# Generated by FakeRAM 2.0 (routing-friendly)
VERSION 5.7 ;
BUSBITCHARS "[]" ;
PROPERTYDEFINITIONS
  MACRO width INTEGER ;
  MACRO depth INTEGER ;
  MACRO banks INTEGER ;
END PROPERTYDEFINITIONS
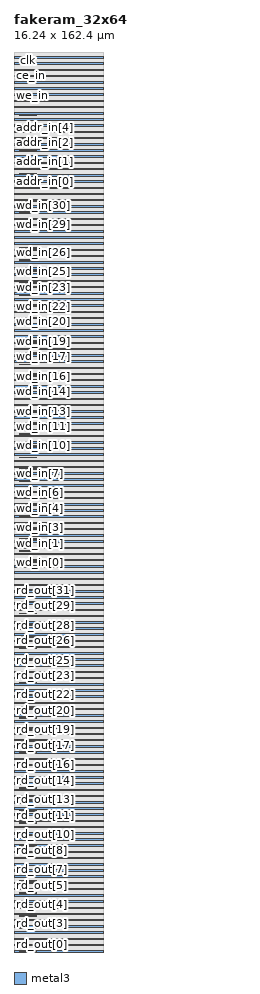
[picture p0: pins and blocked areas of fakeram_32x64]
MACRO fakeram_32x64
  PROPERTY width 32 ;
  PROPERTY depth 64 ;
  PROPERTY banks 1 ;
  FOREIGN fakeram_32x64 0 0 ;
  SYMMETRY X Y R90 ;
  SIZE 16.240 BY 162.400 ;
  CLASS BLOCK ;
  PIN rd_out[0]
    DIRECTION OUTPUT ;
    USE SIGNAL ;
    PORT
      LAYER metal3 ;
      RECT 1.000 0.140 3.000 0.210 ;
    END
    PORT
      LAYER metal3 ;
      RECT 1.000 0.105 4.000 0.245 ;
    END
  END rd_out[0]
  PIN rd_out[1]
    DIRECTION OUTPUT ;
    USE SIGNAL ;
    PORT
      LAYER metal3 ;
      RECT 1.000 2.240 3.000 2.310 ;
    END
    PORT
      LAYER metal3 ;
      RECT 1.000 2.205 4.000 2.345 ;
    END
  END rd_out[1]
  PIN rd_out[2]
    DIRECTION OUTPUT ;
    USE SIGNAL ;
    PORT
      LAYER metal3 ;
      RECT 1.000 4.340 3.000 4.410 ;
    END
    PORT
      LAYER metal3 ;
      RECT 1.000 4.305 4.000 4.445 ;
    END
  END rd_out[2]
  PIN rd_out[3]
    DIRECTION OUTPUT ;
    USE SIGNAL ;
    PORT
      LAYER metal3 ;
      RECT 1.000 6.440 3.000 6.510 ;
    END
    PORT
      LAYER metal3 ;
      RECT 1.000 6.405 4.000 6.545 ;
    END
  END rd_out[3]
  PIN rd_out[4]
    DIRECTION OUTPUT ;
    USE SIGNAL ;
    PORT
      LAYER metal3 ;
      RECT 1.000 8.540 3.000 8.610 ;
    END
    PORT
      LAYER metal3 ;
      RECT 1.000 8.505 4.000 8.645 ;
    END
  END rd_out[4]
  PIN rd_out[5]
    DIRECTION OUTPUT ;
    USE SIGNAL ;
    PORT
      LAYER metal3 ;
      RECT 1.000 10.640 3.000 10.710 ;
    END
    PORT
      LAYER metal3 ;
      RECT 1.000 10.605 4.000 10.745 ;
    END
  END rd_out[5]
  PIN rd_out[6]
    DIRECTION OUTPUT ;
    USE SIGNAL ;
    PORT
      LAYER metal3 ;
      RECT 1.000 12.740 3.000 12.810 ;
    END
    PORT
      LAYER metal3 ;
      RECT 1.000 12.705 4.000 12.845 ;
    END
  END rd_out[6]
  PIN rd_out[7]
    DIRECTION OUTPUT ;
    USE SIGNAL ;
    PORT
      LAYER metal3 ;
      RECT 1.000 14.840 3.000 14.910 ;
    END
    PORT
      LAYER metal3 ;
      RECT 1.000 14.805 4.000 14.945 ;
    END
  END rd_out[7]
  PIN rd_out[8]
    DIRECTION OUTPUT ;
    USE SIGNAL ;
    PORT
      LAYER metal3 ;
      RECT 1.000 16.940 3.000 17.010 ;
    END
    PORT
      LAYER metal3 ;
      RECT 1.000 16.905 4.000 17.045 ;
    END
  END rd_out[8]
  PIN rd_out[9]
    DIRECTION OUTPUT ;
    USE SIGNAL ;
    PORT
      LAYER metal3 ;
      RECT 1.000 19.040 3.000 19.110 ;
    END
    PORT
      LAYER metal3 ;
      RECT 1.000 19.005 4.000 19.145 ;
    END
  END rd_out[9]
  PIN rd_out[10]
    DIRECTION OUTPUT ;
    USE SIGNAL ;
    PORT
      LAYER metal3 ;
      RECT 1.000 21.140 3.000 21.210 ;
    END
    PORT
      LAYER metal3 ;
      RECT 1.000 21.105 4.000 21.245 ;
    END
  END rd_out[10]
  PIN rd_out[11]
    DIRECTION OUTPUT ;
    USE SIGNAL ;
    PORT
      LAYER metal3 ;
      RECT 1.000 23.240 3.000 23.310 ;
    END
    PORT
      LAYER metal3 ;
      RECT 1.000 23.205 4.000 23.345 ;
    END
  END rd_out[11]
  PIN rd_out[12]
    DIRECTION OUTPUT ;
    USE SIGNAL ;
    PORT
      LAYER metal3 ;
      RECT 1.000 25.340 3.000 25.410 ;
    END
    PORT
      LAYER metal3 ;
      RECT 1.000 25.305 4.000 25.445 ;
    END
  END rd_out[12]
  PIN rd_out[13]
    DIRECTION OUTPUT ;
    USE SIGNAL ;
    PORT
      LAYER metal3 ;
      RECT 1.000 27.440 3.000 27.510 ;
    END
    PORT
      LAYER metal3 ;
      RECT 1.000 27.405 4.000 27.545 ;
    END
  END rd_out[13]
  PIN rd_out[14]
    DIRECTION OUTPUT ;
    USE SIGNAL ;
    PORT
      LAYER metal3 ;
      RECT 1.000 29.540 3.000 29.610 ;
    END
    PORT
      LAYER metal3 ;
      RECT 1.000 29.505 4.000 29.645 ;
    END
  END rd_out[14]
  PIN rd_out[15]
    DIRECTION OUTPUT ;
    USE SIGNAL ;
    PORT
      LAYER metal3 ;
      RECT 1.000 31.640 3.000 31.710 ;
    END
    PORT
      LAYER metal3 ;
      RECT 1.000 31.605 4.000 31.745 ;
    END
  END rd_out[15]
  PIN rd_out[16]
    DIRECTION OUTPUT ;
    USE SIGNAL ;
    PORT
      LAYER metal3 ;
      RECT 1.000 33.740 3.000 33.810 ;
    END
    PORT
      LAYER metal3 ;
      RECT 1.000 33.705 4.000 33.845 ;
    END
  END rd_out[16]
  PIN rd_out[17]
    DIRECTION OUTPUT ;
    USE SIGNAL ;
    PORT
      LAYER metal3 ;
      RECT 1.000 35.840 3.000 35.910 ;
    END
    PORT
      LAYER metal3 ;
      RECT 1.000 35.805 4.000 35.945 ;
    END
  END rd_out[17]
  PIN rd_out[18]
    DIRECTION OUTPUT ;
    USE SIGNAL ;
    PORT
      LAYER metal3 ;
      RECT 1.000 37.940 3.000 38.010 ;
    END
    PORT
      LAYER metal3 ;
      RECT 1.000 37.905 4.000 38.045 ;
    END
  END rd_out[18]
  PIN rd_out[19]
    DIRECTION OUTPUT ;
    USE SIGNAL ;
    PORT
      LAYER metal3 ;
      RECT 1.000 40.040 3.000 40.110 ;
    END
    PORT
      LAYER metal3 ;
      RECT 1.000 40.005 4.000 40.145 ;
    END
  END rd_out[19]
  PIN rd_out[20]
    DIRECTION OUTPUT ;
    USE SIGNAL ;
    PORT
      LAYER metal3 ;
      RECT 1.000 42.140 3.000 42.210 ;
    END
    PORT
      LAYER metal3 ;
      RECT 1.000 42.105 4.000 42.245 ;
    END
  END rd_out[20]
  PIN rd_out[21]
    DIRECTION OUTPUT ;
    USE SIGNAL ;
    PORT
      LAYER metal3 ;
      RECT 1.000 44.240 3.000 44.310 ;
    END
    PORT
      LAYER metal3 ;
      RECT 1.000 44.205 4.000 44.345 ;
    END
  END rd_out[21]
  PIN rd_out[22]
    DIRECTION OUTPUT ;
    USE SIGNAL ;
    PORT
      LAYER metal3 ;
      RECT 1.000 46.340 3.000 46.410 ;
    END
    PORT
      LAYER metal3 ;
      RECT 1.000 46.305 4.000 46.445 ;
    END
  END rd_out[22]
  PIN rd_out[23]
    DIRECTION OUTPUT ;
    USE SIGNAL ;
    PORT
      LAYER metal3 ;
      RECT 1.000 48.440 3.000 48.510 ;
    END
    PORT
      LAYER metal3 ;
      RECT 1.000 48.405 4.000 48.545 ;
    END
  END rd_out[23]
  PIN rd_out[24]
    DIRECTION OUTPUT ;
    USE SIGNAL ;
    PORT
      LAYER metal3 ;
      RECT 1.000 50.540 3.000 50.610 ;
    END
    PORT
      LAYER metal3 ;
      RECT 1.000 50.505 4.000 50.645 ;
    END
  END rd_out[24]
  PIN rd_out[25]
    DIRECTION OUTPUT ;
    USE SIGNAL ;
    PORT
      LAYER metal3 ;
      RECT 1.000 52.640 3.000 52.710 ;
    END
    PORT
      LAYER metal3 ;
      RECT 1.000 52.605 4.000 52.745 ;
    END
  END rd_out[25]
  PIN rd_out[26]
    DIRECTION OUTPUT ;
    USE SIGNAL ;
    PORT
      LAYER metal3 ;
      RECT 1.000 54.740 3.000 54.810 ;
    END
    PORT
      LAYER metal3 ;
      RECT 1.000 54.705 4.000 54.845 ;
    END
  END rd_out[26]
  PIN rd_out[27]
    DIRECTION OUTPUT ;
    USE SIGNAL ;
    PORT
      LAYER metal3 ;
      RECT 1.000 56.840 3.000 56.910 ;
    END
    PORT
      LAYER metal3 ;
      RECT 1.000 56.805 4.000 56.945 ;
    END
  END rd_out[27]
  PIN rd_out[28]
    DIRECTION OUTPUT ;
    USE SIGNAL ;
    PORT
      LAYER metal3 ;
      RECT 1.000 58.940 3.000 59.010 ;
    END
    PORT
      LAYER metal3 ;
      RECT 1.000 58.905 4.000 59.045 ;
    END
  END rd_out[28]
  PIN rd_out[29]
    DIRECTION OUTPUT ;
    USE SIGNAL ;
    PORT
      LAYER metal3 ;
      RECT 1.000 61.040 3.000 61.110 ;
    END
    PORT
      LAYER metal3 ;
      RECT 1.000 61.005 4.000 61.145 ;
    END
  END rd_out[29]
  PIN rd_out[30]
    DIRECTION OUTPUT ;
    USE SIGNAL ;
    PORT
      LAYER metal3 ;
      RECT 1.000 63.140 3.000 63.210 ;
    END
    PORT
      LAYER metal3 ;
      RECT 1.000 63.105 4.000 63.245 ;
    END
  END rd_out[30]
  PIN rd_out[31]
    DIRECTION OUTPUT ;
    USE SIGNAL ;
    PORT
      LAYER metal3 ;
      RECT 1.000 65.240 3.000 65.310 ;
    END
    PORT
      LAYER metal3 ;
      RECT 1.000 65.205 4.000 65.345 ;
    END
  END rd_out[31]
  PIN wd_in[0]
    DIRECTION INPUT ;
    USE SIGNAL ;
    PORT
      LAYER metal3 ;
      RECT 1.000 70.280 3.000 70.350 ;
    END
    PORT
      LAYER metal3 ;
      RECT 1.000 70.245 4.000 70.385 ;
    END
  END wd_in[0]
  PIN wd_in[1]
    DIRECTION INPUT ;
    USE SIGNAL ;
    PORT
      LAYER metal3 ;
      RECT 1.000 72.380 3.000 72.450 ;
    END
    PORT
      LAYER metal3 ;
      RECT 1.000 72.345 4.000 72.485 ;
    END
  END wd_in[1]
  PIN wd_in[2]
    DIRECTION INPUT ;
    USE SIGNAL ;
    PORT
      LAYER metal3 ;
      RECT 1.000 74.480 3.000 74.550 ;
    END
    PORT
      LAYER metal3 ;
      RECT 1.000 74.445 4.000 74.585 ;
    END
  END wd_in[2]
  PIN wd_in[3]
    DIRECTION INPUT ;
    USE SIGNAL ;
    PORT
      LAYER metal3 ;
      RECT 1.000 76.580 3.000 76.650 ;
    END
    PORT
      LAYER metal3 ;
      RECT 1.000 76.545 4.000 76.685 ;
    END
  END wd_in[3]
  PIN wd_in[4]
    DIRECTION INPUT ;
    USE SIGNAL ;
    PORT
      LAYER metal3 ;
      RECT 1.000 78.680 3.000 78.750 ;
    END
    PORT
      LAYER metal3 ;
      RECT 1.000 78.645 4.000 78.785 ;
    END
  END wd_in[4]
  PIN wd_in[5]
    DIRECTION INPUT ;
    USE SIGNAL ;
    PORT
      LAYER metal3 ;
      RECT 1.000 80.780 3.000 80.850 ;
    END
    PORT
      LAYER metal3 ;
      RECT 1.000 80.745 4.000 80.885 ;
    END
  END wd_in[5]
  PIN wd_in[6]
    DIRECTION INPUT ;
    USE SIGNAL ;
    PORT
      LAYER metal3 ;
      RECT 1.000 82.880 3.000 82.950 ;
    END
    PORT
      LAYER metal3 ;
      RECT 1.000 82.845 4.000 82.985 ;
    END
  END wd_in[6]
  PIN wd_in[7]
    DIRECTION INPUT ;
    USE SIGNAL ;
    PORT
      LAYER metal3 ;
      RECT 1.000 84.980 3.000 85.050 ;
    END
    PORT
      LAYER metal3 ;
      RECT 1.000 84.945 4.000 85.085 ;
    END
  END wd_in[7]
  PIN wd_in[8]
    DIRECTION INPUT ;
    USE SIGNAL ;
    PORT
      LAYER metal3 ;
      RECT 1.000 87.080 3.000 87.150 ;
    END
    PORT
      LAYER metal3 ;
      RECT 1.000 87.045 4.000 87.185 ;
    END
  END wd_in[8]
  PIN wd_in[9]
    DIRECTION INPUT ;
    USE SIGNAL ;
    PORT
      LAYER metal3 ;
      RECT 1.000 89.180 3.000 89.250 ;
    END
    PORT
      LAYER metal3 ;
      RECT 1.000 89.145 4.000 89.285 ;
    END
  END wd_in[9]
  PIN wd_in[10]
    DIRECTION INPUT ;
    USE SIGNAL ;
    PORT
      LAYER metal3 ;
      RECT 1.000 91.280 3.000 91.350 ;
    END
    PORT
      LAYER metal3 ;
      RECT 1.000 91.245 4.000 91.385 ;
    END
  END wd_in[10]
  PIN wd_in[11]
    DIRECTION INPUT ;
    USE SIGNAL ;
    PORT
      LAYER metal3 ;
      RECT 1.000 93.380 3.000 93.450 ;
    END
    PORT
      LAYER metal3 ;
      RECT 1.000 93.345 4.000 93.485 ;
    END
  END wd_in[11]
  PIN wd_in[12]
    DIRECTION INPUT ;
    USE SIGNAL ;
    PORT
      LAYER metal3 ;
      RECT 1.000 95.480 3.000 95.550 ;
    END
    PORT
      LAYER metal3 ;
      RECT 1.000 95.445 4.000 95.585 ;
    END
  END wd_in[12]
  PIN wd_in[13]
    DIRECTION INPUT ;
    USE SIGNAL ;
    PORT
      LAYER metal3 ;
      RECT 1.000 97.580 3.000 97.650 ;
    END
    PORT
      LAYER metal3 ;
      RECT 1.000 97.545 4.000 97.685 ;
    END
  END wd_in[13]
  PIN wd_in[14]
    DIRECTION INPUT ;
    USE SIGNAL ;
    PORT
      LAYER metal3 ;
      RECT 1.000 99.680 3.000 99.750 ;
    END
    PORT
      LAYER metal3 ;
      RECT 1.000 99.645 4.000 99.785 ;
    END
  END wd_in[14]
  PIN wd_in[15]
    DIRECTION INPUT ;
    USE SIGNAL ;
    PORT
      LAYER metal3 ;
      RECT 1.000 101.780 3.000 101.850 ;
    END
    PORT
      LAYER metal3 ;
      RECT 1.000 101.745 4.000 101.885 ;
    END
  END wd_in[15]
  PIN wd_in[16]
    DIRECTION INPUT ;
    USE SIGNAL ;
    PORT
      LAYER metal3 ;
      RECT 1.000 103.880 3.000 103.950 ;
    END
    PORT
      LAYER metal3 ;
      RECT 1.000 103.845 4.000 103.985 ;
    END
  END wd_in[16]
  PIN wd_in[17]
    DIRECTION INPUT ;
    USE SIGNAL ;
    PORT
      LAYER metal3 ;
      RECT 1.000 105.980 3.000 106.050 ;
    END
    PORT
      LAYER metal3 ;
      RECT 1.000 105.945 4.000 106.085 ;
    END
  END wd_in[17]
  PIN wd_in[18]
    DIRECTION INPUT ;
    USE SIGNAL ;
    PORT
      LAYER metal3 ;
      RECT 1.000 108.080 3.000 108.150 ;
    END
    PORT
      LAYER metal3 ;
      RECT 1.000 108.045 4.000 108.185 ;
    END
  END wd_in[18]
  PIN wd_in[19]
    DIRECTION INPUT ;
    USE SIGNAL ;
    PORT
      LAYER metal3 ;
      RECT 1.000 110.180 3.000 110.250 ;
    END
    PORT
      LAYER metal3 ;
      RECT 1.000 110.145 4.000 110.285 ;
    END
  END wd_in[19]
  PIN wd_in[20]
    DIRECTION INPUT ;
    USE SIGNAL ;
    PORT
      LAYER metal3 ;
      RECT 1.000 112.280 3.000 112.350 ;
    END
    PORT
      LAYER metal3 ;
      RECT 1.000 112.245 4.000 112.385 ;
    END
  END wd_in[20]
  PIN wd_in[21]
    DIRECTION INPUT ;
    USE SIGNAL ;
    PORT
      LAYER metal3 ;
      RECT 1.000 114.380 3.000 114.450 ;
    END
    PORT
      LAYER metal3 ;
      RECT 1.000 114.345 4.000 114.485 ;
    END
  END wd_in[21]
  PIN wd_in[22]
    DIRECTION INPUT ;
    USE SIGNAL ;
    PORT
      LAYER metal3 ;
      RECT 1.000 116.480 3.000 116.550 ;
    END
    PORT
      LAYER metal3 ;
      RECT 1.000 116.445 4.000 116.585 ;
    END
  END wd_in[22]
  PIN wd_in[23]
    DIRECTION INPUT ;
    USE SIGNAL ;
    PORT
      LAYER metal3 ;
      RECT 1.000 118.580 3.000 118.650 ;
    END
    PORT
      LAYER metal3 ;
      RECT 1.000 118.545 4.000 118.685 ;
    END
  END wd_in[23]
  PIN wd_in[24]
    DIRECTION INPUT ;
    USE SIGNAL ;
    PORT
      LAYER metal3 ;
      RECT 1.000 120.680 3.000 120.750 ;
    END
    PORT
      LAYER metal3 ;
      RECT 1.000 120.645 4.000 120.785 ;
    END
  END wd_in[24]
  PIN wd_in[25]
    DIRECTION INPUT ;
    USE SIGNAL ;
    PORT
      LAYER metal3 ;
      RECT 1.000 122.780 3.000 122.850 ;
    END
    PORT
      LAYER metal3 ;
      RECT 1.000 122.745 4.000 122.885 ;
    END
  END wd_in[25]
  PIN wd_in[26]
    DIRECTION INPUT ;
    USE SIGNAL ;
    PORT
      LAYER metal3 ;
      RECT 1.000 124.880 3.000 124.950 ;
    END
    PORT
      LAYER metal3 ;
      RECT 1.000 124.845 4.000 124.985 ;
    END
  END wd_in[26]
  PIN wd_in[27]
    DIRECTION INPUT ;
    USE SIGNAL ;
    PORT
      LAYER metal3 ;
      RECT 1.000 126.980 3.000 127.050 ;
    END
    PORT
      LAYER metal3 ;
      RECT 1.000 126.945 4.000 127.085 ;
    END
  END wd_in[27]
  PIN wd_in[28]
    DIRECTION INPUT ;
    USE SIGNAL ;
    PORT
      LAYER metal3 ;
      RECT 1.000 129.080 3.000 129.150 ;
    END
    PORT
      LAYER metal3 ;
      RECT 1.000 129.045 4.000 129.185 ;
    END
  END wd_in[28]
  PIN wd_in[29]
    DIRECTION INPUT ;
    USE SIGNAL ;
    PORT
      LAYER metal3 ;
      RECT 1.000 131.180 3.000 131.250 ;
    END
    PORT
      LAYER metal3 ;
      RECT 1.000 131.145 4.000 131.285 ;
    END
  END wd_in[29]
  PIN wd_in[30]
    DIRECTION INPUT ;
    USE SIGNAL ;
    PORT
      LAYER metal3 ;
      RECT 1.000 133.280 3.000 133.350 ;
    END
    PORT
      LAYER metal3 ;
      RECT 1.000 133.245 4.000 133.385 ;
    END
  END wd_in[30]
  PIN wd_in[31]
    DIRECTION INPUT ;
    USE SIGNAL ;
    PORT
      LAYER metal3 ;
      RECT 1.000 135.380 3.000 135.450 ;
    END
    PORT
      LAYER metal3 ;
      RECT 1.000 135.345 4.000 135.485 ;
    END
  END wd_in[31]
  PIN addr_in[0]
    DIRECTION INPUT ;
    USE SIGNAL ;
    PORT
      LAYER metal3 ;
      RECT 1.000 140.420 3.000 140.490 ;
    END
    PORT
      LAYER metal3 ;
      RECT 1.000 140.385 4.000 140.525 ;
    END
  END addr_in[0]
  PIN addr_in[1]
    DIRECTION INPUT ;
    USE SIGNAL ;
    PORT
      LAYER metal3 ;
      RECT 1.000 142.520 3.000 142.590 ;
    END
    PORT
      LAYER metal3 ;
      RECT 1.000 142.485 4.000 142.625 ;
    END
  END addr_in[1]
  PIN addr_in[2]
    DIRECTION INPUT ;
    USE SIGNAL ;
    PORT
      LAYER metal3 ;
      RECT 1.000 144.620 3.000 144.690 ;
    END
    PORT
      LAYER metal3 ;
      RECT 1.000 144.585 4.000 144.725 ;
    END
  END addr_in[2]
  PIN addr_in[3]
    DIRECTION INPUT ;
    USE SIGNAL ;
    PORT
      LAYER metal3 ;
      RECT 1.000 146.720 3.000 146.790 ;
    END
    PORT
      LAYER metal3 ;
      RECT 1.000 146.685 4.000 146.825 ;
    END
  END addr_in[3]
  PIN addr_in[4]
    DIRECTION INPUT ;
    USE SIGNAL ;
    PORT
      LAYER metal3 ;
      RECT 1.000 148.820 3.000 148.890 ;
    END
    PORT
      LAYER metal3 ;
      RECT 1.000 148.785 4.000 148.925 ;
    END
  END addr_in[4]
  PIN addr_in[5]
    DIRECTION INPUT ;
    USE SIGNAL ;
    PORT
      LAYER metal3 ;
      RECT 1.000 150.920 3.000 150.990 ;
    END
    PORT
      LAYER metal3 ;
      RECT 1.000 150.885 4.000 151.025 ;
    END
  END addr_in[5]
  PIN we_in
    DIRECTION INPUT ;
    USE SIGNAL ;
    PORT
      LAYER metal3 ;
      RECT 1.000 155.960 3.000 156.030 ;
    END
    PORT
      LAYER metal3 ;
      RECT 1.000 155.925 4.000 156.065 ;
    END
  END we_in
  PIN ce_in
    DIRECTION INPUT ;
    USE SIGNAL ;
    PORT
      LAYER metal3 ;
      RECT 1.000 158.060 3.000 158.130 ;
    END
    PORT
      LAYER metal3 ;
      RECT 1.000 158.025 4.000 158.165 ;
    END
  END ce_in
  PIN clk
    DIRECTION INPUT ;
    USE SIGNAL ;
    PORT
      LAYER metal3 ;
      RECT 1.000 160.160 3.000 160.230 ;
    END
    PORT
      LAYER metal3 ;
      RECT 1.000 160.125 4.000 160.265 ;
    END
  END clk
  PIN VSS
    DIRECTION INOUT ;
    USE GROUND ;
    PORT
      LAYER metal3 ;
      RECT 0.140 0.000 16.100 0.280 ;
      RECT 0.140 2.240 16.100 2.520 ;
      RECT 0.140 4.480 16.100 4.760 ;
      RECT 0.140 6.720 16.100 7.000 ;
      RECT 0.140 8.960 16.100 9.240 ;
      RECT 0.140 11.200 16.100 11.480 ;
      RECT 0.140 13.440 16.100 13.720 ;
      RECT 0.140 15.680 16.100 15.960 ;
      RECT 0.140 17.920 16.100 18.200 ;
      RECT 0.140 20.160 16.100 20.440 ;
      RECT 0.140 22.400 16.100 22.680 ;
      RECT 0.140 24.640 16.100 24.920 ;
      RECT 0.140 26.880 16.100 27.160 ;
      RECT 0.140 29.120 16.100 29.400 ;
      RECT 0.140 31.360 16.100 31.640 ;
      RECT 0.140 33.600 16.100 33.880 ;
      RECT 0.140 35.840 16.100 36.120 ;
      RECT 0.140 38.080 16.100 38.360 ;
      RECT 0.140 40.320 16.100 40.600 ;
      RECT 0.140 42.560 16.100 42.840 ;
      RECT 0.140 44.800 16.100 45.080 ;
      RECT 0.140 47.040 16.100 47.320 ;
      RECT 0.140 49.280 16.100 49.560 ;
      RECT 0.140 51.520 16.100 51.800 ;
      RECT 0.140 53.760 16.100 54.040 ;
      RECT 0.140 56.000 16.100 56.280 ;
      RECT 0.140 58.240 16.100 58.520 ;
      RECT 0.140 60.480 16.100 60.760 ;
      RECT 0.140 62.720 16.100 63.000 ;
      RECT 0.140 64.960 16.100 65.240 ;
      RECT 0.140 67.200 16.100 67.480 ;
      RECT 0.140 69.440 16.100 69.720 ;
      RECT 0.140 71.680 16.100 71.960 ;
      RECT 0.140 73.920 16.100 74.200 ;
      RECT 0.140 76.160 16.100 76.440 ;
      RECT 0.140 78.400 16.100 78.680 ;
      RECT 0.140 80.640 16.100 80.920 ;
      RECT 0.140 82.880 16.100 83.160 ;
      RECT 0.140 85.120 16.100 85.400 ;
      RECT 0.140 87.360 16.100 87.640 ;
      RECT 0.140 89.600 16.100 89.880 ;
      RECT 0.140 91.840 16.100 92.120 ;
      RECT 0.140 94.080 16.100 94.360 ;
      RECT 0.140 96.320 16.100 96.600 ;
      RECT 0.140 98.560 16.100 98.840 ;
      RECT 0.140 100.800 16.100 101.080 ;
      RECT 0.140 103.040 16.100 103.320 ;
      RECT 0.140 105.280 16.100 105.560 ;
      RECT 0.140 107.520 16.100 107.800 ;
      RECT 0.140 109.760 16.100 110.040 ;
      RECT 0.140 112.000 16.100 112.280 ;
      RECT 0.140 114.240 16.100 114.520 ;
      RECT 0.140 116.480 16.100 116.760 ;
      RECT 0.140 118.720 16.100 119.000 ;
      RECT 0.140 120.960 16.100 121.240 ;
      RECT 0.140 123.200 16.100 123.480 ;
      RECT 0.140 125.440 16.100 125.720 ;
      RECT 0.140 127.680 16.100 127.960 ;
      RECT 0.140 129.920 16.100 130.200 ;
      RECT 0.140 132.160 16.100 132.440 ;
      RECT 0.140 134.400 16.100 134.680 ;
      RECT 0.140 136.640 16.100 136.920 ;
      RECT 0.140 138.880 16.100 139.160 ;
      RECT 0.140 141.120 16.100 141.400 ;
      RECT 0.140 143.360 16.100 143.640 ;
      RECT 0.140 145.600 16.100 145.880 ;
      RECT 0.140 147.840 16.100 148.120 ;
      RECT 0.140 150.080 16.100 150.360 ;
      RECT 0.140 152.320 16.100 152.600 ;
      RECT 0.140 154.560 16.100 154.840 ;
      RECT 0.140 156.800 16.100 157.080 ;
      RECT 0.140 159.040 16.100 159.320 ;
      RECT 0.140 161.280 16.100 161.560 ;
    END
  END VSS
  PIN VDD
    DIRECTION INOUT ;
    USE POWER ;
    PORT
      LAYER metal3 ;
      RECT 0.140 1.120 16.100 1.400 ;
      RECT 0.140 3.360 16.100 3.640 ;
      RECT 0.140 5.600 16.100 5.880 ;
      RECT 0.140 7.840 16.100 8.120 ;
      RECT 0.140 10.080 16.100 10.360 ;
      RECT 0.140 12.320 16.100 12.600 ;
      RECT 0.140 14.560 16.100 14.840 ;
      RECT 0.140 16.800 16.100 17.080 ;
      RECT 0.140 19.040 16.100 19.320 ;
      RECT 0.140 21.280 16.100 21.560 ;
      RECT 0.140 23.520 16.100 23.800 ;
      RECT 0.140 25.760 16.100 26.040 ;
      RECT 0.140 28.000 16.100 28.280 ;
      RECT 0.140 30.240 16.100 30.520 ;
      RECT 0.140 32.480 16.100 32.760 ;
      RECT 0.140 34.720 16.100 35.000 ;
      RECT 0.140 36.960 16.100 37.240 ;
      RECT 0.140 39.200 16.100 39.480 ;
      RECT 0.140 41.440 16.100 41.720 ;
      RECT 0.140 43.680 16.100 43.960 ;
      RECT 0.140 45.920 16.100 46.200 ;
      RECT 0.140 48.160 16.100 48.440 ;
      RECT 0.140 50.400 16.100 50.680 ;
      RECT 0.140 52.640 16.100 52.920 ;
      RECT 0.140 54.880 16.100 55.160 ;
      RECT 0.140 57.120 16.100 57.400 ;
      RECT 0.140 59.360 16.100 59.640 ;
      RECT 0.140 61.600 16.100 61.880 ;
      RECT 0.140 63.840 16.100 64.120 ;
      RECT 0.140 66.080 16.100 66.360 ;
      RECT 0.140 68.320 16.100 68.600 ;
      RECT 0.140 70.560 16.100 70.840 ;
      RECT 0.140 72.800 16.100 73.080 ;
      RECT 0.140 75.040 16.100 75.320 ;
      RECT 0.140 77.280 16.100 77.560 ;
      RECT 0.140 79.520 16.100 79.800 ;
      RECT 0.140 81.760 16.100 82.040 ;
      RECT 0.140 84.000 16.100 84.280 ;
      RECT 0.140 86.240 16.100 86.520 ;
      RECT 0.140 88.480 16.100 88.760 ;
      RECT 0.140 90.720 16.100 91.000 ;
      RECT 0.140 92.960 16.100 93.240 ;
      RECT 0.140 95.200 16.100 95.480 ;
      RECT 0.140 97.440 16.100 97.720 ;
      RECT 0.140 99.680 16.100 99.960 ;
      RECT 0.140 101.920 16.100 102.200 ;
      RECT 0.140 104.160 16.100 104.440 ;
      RECT 0.140 106.400 16.100 106.680 ;
      RECT 0.140 108.640 16.100 108.920 ;
      RECT 0.140 110.880 16.100 111.160 ;
      RECT 0.140 113.120 16.100 113.400 ;
      RECT 0.140 115.360 16.100 115.640 ;
      RECT 0.140 117.600 16.100 117.880 ;
      RECT 0.140 119.840 16.100 120.120 ;
      RECT 0.140 122.080 16.100 122.360 ;
      RECT 0.140 124.320 16.100 124.600 ;
      RECT 0.140 126.560 16.100 126.840 ;
      RECT 0.140 128.800 16.100 129.080 ;
      RECT 0.140 131.040 16.100 131.320 ;
      RECT 0.140 133.280 16.100 133.560 ;
      RECT 0.140 135.520 16.100 135.800 ;
      RECT 0.140 137.760 16.100 138.040 ;
      RECT 0.140 140.000 16.100 140.280 ;
      RECT 0.140 142.240 16.100 142.520 ;
      RECT 0.140 144.480 16.100 144.760 ;
      RECT 0.140 146.720 16.100 147.000 ;
      RECT 0.140 148.960 16.100 149.240 ;
      RECT 0.140 151.200 16.100 151.480 ;
      RECT 0.140 153.440 16.100 153.720 ;
      RECT 0.140 155.680 16.100 155.960 ;
      RECT 0.140 157.920 16.100 158.200 ;
      RECT 0.140 160.160 16.100 160.440 ;
    END
  END VDD
  OBS
    LAYER metal1 ;
    RECT 0 0 16.240 162.400 ;
    LAYER metal2 ;
    RECT 0 0 16.240 162.400 ;
  END
END fakeram_32x64
END LIBRARY
